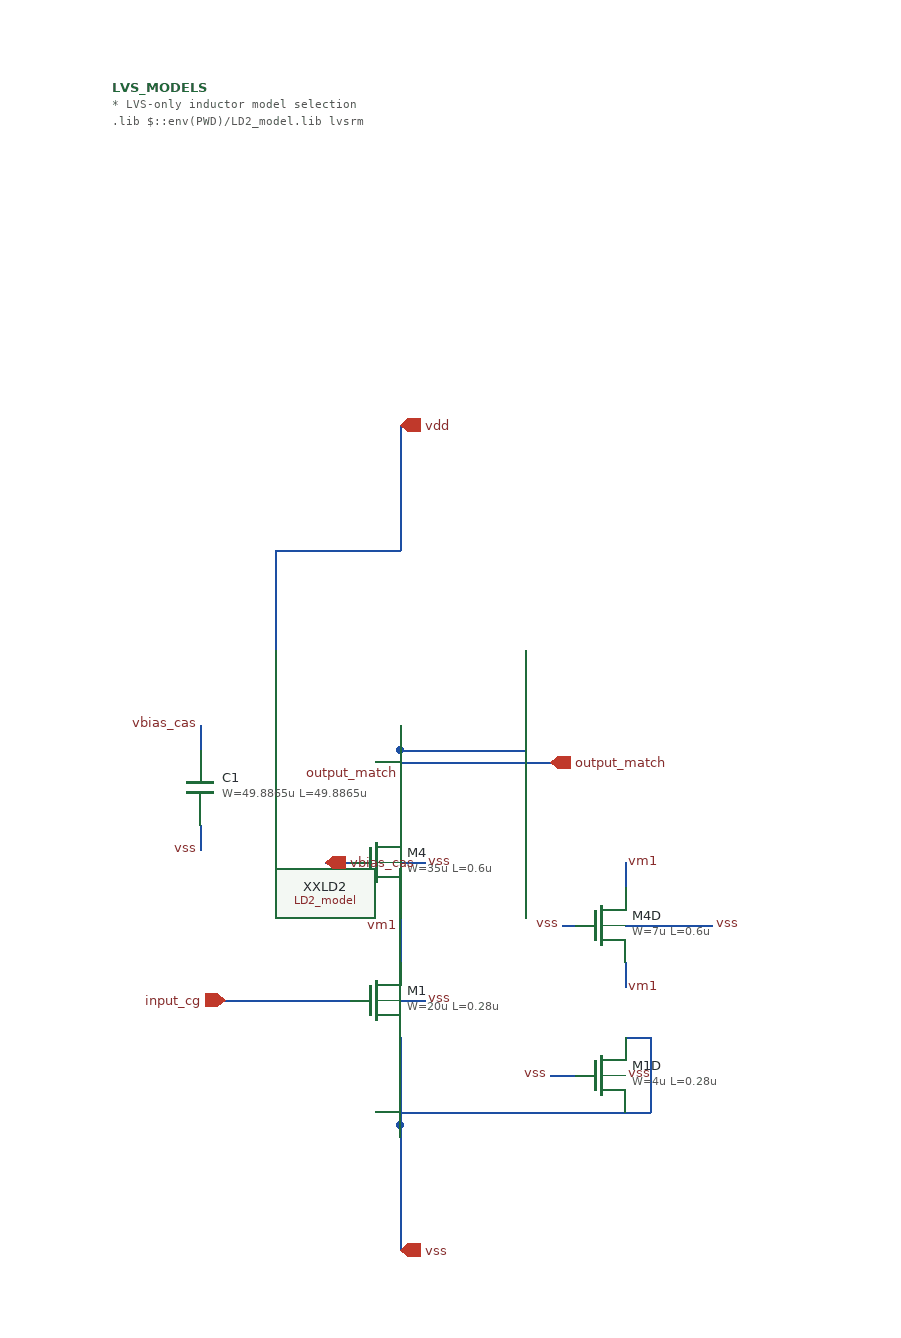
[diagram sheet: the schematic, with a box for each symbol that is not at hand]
v {xschem version=3.4.8RC file_version=1.3}
G {}
K {}
V {}
S {}
F {}
E {}
N 290 -330 310 -330 {
lab=vss}
N 290 -300 290 -290 {
lab=vss}
N 230 -330 250 -330 {
lab=input_cg}
N 290 -290 290 -230 {
lab=vss}
N 290 -440 310 -440 {
lab=vss}
N 290 -410 290 -400 {
lab=vm1}
N 230 -440 250 -440 {
lab=vbias_cas}
N 130 -550 130 -530 {lab=vbias_cas}
N 130 -470 130 -450 {lab=vss}
N 290 -400 290 -360 {
lab=vm1}
N 290 -230 290 -220 {
lab=vss}
N 290 -160 290 -150 {
lab=vss}
N 290 -150 290 -130 {
lab=vss}
N 290 -520 360 -520 {
lab=output_match}
N 290 -710 290 -690 {lab=vdd}
N 190 -690 190 -610 {lab=vdd}
N 190 -690 290 -690 {lab=vdd}
N 390 -610 390 -530 {lab=output_match}
N 290 -530 390 -530 {lab=output_match}
N 290 -550 290 -530 {lab=output_match}
N 290 -790 290 -730 {lab=vdd}
N 290 -530 290 -470 {lab=output_match}
N 290 -725 290 -710 {lab=vdd}
N 290 -730 290 -725 {lab=vdd}
N 150 -330 230 -330 {lab=input_cg}
N 360 -520 410 -520 {lab=output_match}
N 290 -240 470 -240 {lab=vss}
N 470 -300 490 -300 {lab=vss}
N 490 -300 490 -240 {lab=vss}
N 470 -240 490 -240 {lab=vss}
N 410 -270 430 -270 {lab=vss}
N 470 -440 470 -420 {lab=vm1}
N 470 -360 470 -340 {lab=vm1}
N 470 -390 540 -390 {lab=vss}
N 420 -390 430 -390 {lab=vss}
N 290 -230 290 -160 {lab=vss}
C {symbols/nfet_05v0.sym} 270 -440 0 0 {name=M4
L=0.6u
W=35u
nf=10
m=4
ad="'int((nf+1)/2) * W/nf * 0.18u'"
pd="'2*int((nf+1)/2) * (W/nf + 0.18u)'"
as="'int((nf+2)/2) * W/nf * 0.18u'"
ps="'2*int((nf+2)/2) * (W/nf + 0.18u)'"
nrd="'0.18u / W'" nrs="'0.18u / W'"
sa=0 sb=0 sd=0
model=nfet_05v0
spiceprefix=X
}
C {symbols/nfet_03v3.sym} 270 -330 0 0 {name=M1
L=0.28u
W=20u
nf=10
m=10
ad="'int((nf+1)/2) * W/nf * 0.18u'"
pd="'2*int((nf+1)/2) * (W/nf + 0.18u)'"
as="'int((nf+2)/2) * W/nf * 0.18u'"
ps="'2*int((nf+2)/2) * (W/nf + 0.18u)'"
nrd="'0.18u / W'" nrs="'0.18u / W'"
sa=0 sb=0 sd=0
model=nfet_03v3
spiceprefix=X
}
C {lab_pin.sym} 290 -510 0 0 {name=p36 sig_type=std_logic lab=output_match
}
C {lab_pin.sym} 290 -388.75 0 0 {name=p72 sig_type=std_logic lab=vm1}
C {LD2_model.sym} 290 -610 0 0 {name=XXLD2}
C {iopin.sym} 230 -440 0 1 {name=p61 lab=vbias_cas}
C {lab_pin.sym} 310 -440 2 0 {name=p41 sig_type=std_logic lab=vss}
C {lab_pin.sym} 310 -330 2 0 {name=p42 sig_type=std_logic lab=vss}
C {ipin.sym} 150 -330 0 0 {name=p1 lab=input_cg}
C {opin.sym} 410 -520 0 0 {name=p2 lab=output_match}
C {iopin.sym} 290 -790 1 1 {name=p3 lab=vdd}
C {iopin.sym} 290 -130 3 1 {name=p4 lab=vss}
C {symbols/nfet_03v3.sym} 450 -270 0 0 {name=M1D
L=0.28u
W=4u
nf=2
m=2
ad="'int((nf+1)/2) * W/nf * 0.18u'"
pd="'2*int((nf+1)/2) * (W/nf + 0.18u)'"
as="'int((nf+2)/2) * W/nf * 0.18u'"
ps="'2*int((nf+2)/2) * (W/nf + 0.18u)'"
nrd="'0.18u / W'" nrs="'0.18u / W'"
sa=0 sb=0 sd=0
model=nfet_03v3
spiceprefix=X
}
C {lab_pin.sym} 410 -270 0 0 {name=pM1D_g sig_type=std_logic lab=vss}
C {lab_pin.sym} 470 -270 2 0 {name=pM1D_b sig_type=std_logic lab=vss}
C {symbols/cap_mim_2f0fF.sym} 130 -500 2 1 {name=C1
W=49.8865u
L=49.8865u
model=cap_mim_2f0_m4m5_noshield
spiceprefix=X
m=4}
C {lab_pin.sym} 130 -550 0 0 {name=pC1_cas sig_type=std_logic lab=vbias_cas}
C {lab_pin.sym} 130 -450 3 0 {name=pC1_vss sig_type=std_logic lab=vss}
C {symbols/nfet_05v0.sym} 450 -390 0 0 {name=M4D
L=0.6u
W=7u
nf=2
m=2
ad="'int((nf+1)/2) * W/nf * 0.18u'"
pd="'2*int((nf+1)/2) * (W/nf + 0.18u)'"
as="'int((nf+2)/2) * W/nf * 0.18u'"
ps="'2*int((nf+2)/2) * (W/nf + 0.18u)'"
nrd="'0.18u / W'" nrs="'0.18u / W'"
sa=0 sb=0 sd=0
model=nfet_05v0
spiceprefix=X
}
C {lab_pin.sym} 470 -440 2 0 {name=pM4D_d sig_type=std_logic lab=vm1}
C {lab_pin.sym} 470 -340 2 0 {name=pM4D_s sig_type=std_logic lab=vm1}
C {lab_pin.sym} 420 -390 0 0 {name=pM4D_g sig_type=std_logic lab=vss}
C {lab_pin.sym} 540 -390 2 0 {name=pM4D_b sig_type=std_logic lab=vss}
C {code_shown.sym} 60 -1060 0 0 {name=LVS_MODELS only_toplevel=true
format="tcleval( @value )"
value="
* LVS-only inductor model selection
.lib $::env(PWD)/LD2_model.lib lvsrm
"}
